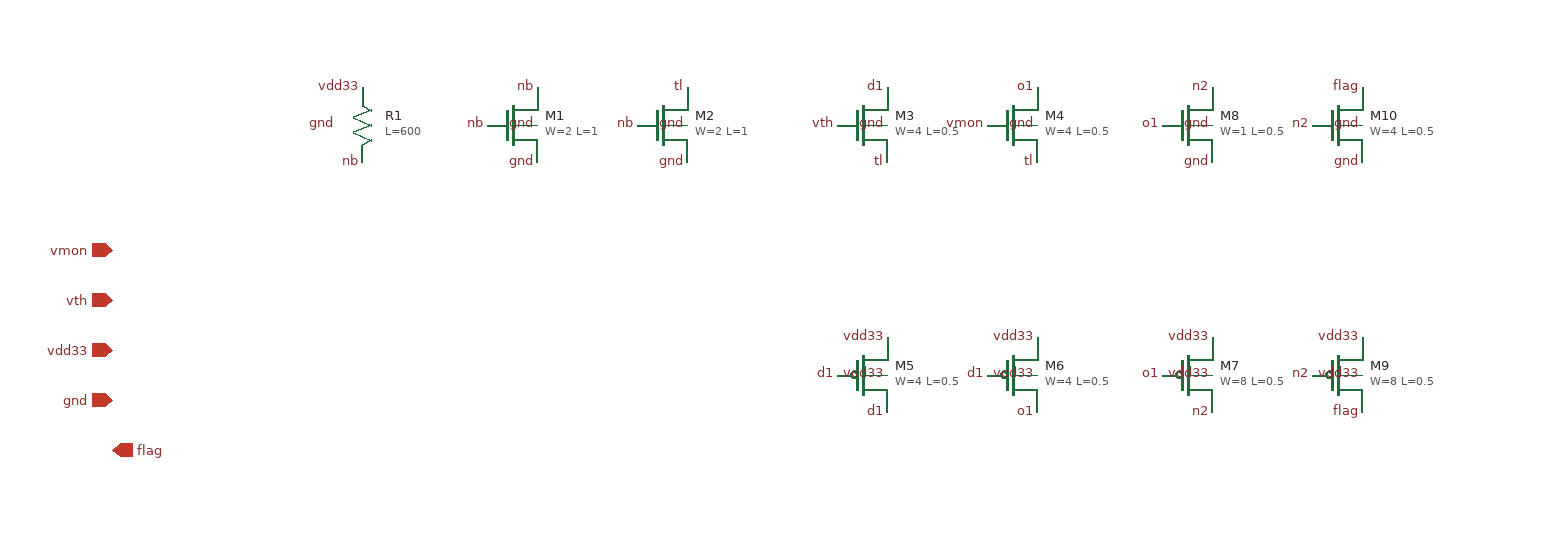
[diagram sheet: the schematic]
v {xschem version=3.4.7 file_version=1.2
}
G {}
K {}
V {}
S {}
E {}
C {sky130_fd_pr/res_xhigh_po_1p41.sym} 0 0 0 0 {name=R1 L=600 model=res_xhigh_po_1p41 spiceprefix=X mult=1}
C {devices/lab_pin.sym} 0 -30 0 0 {name=p1 sig_type=std_logic lab=vdd33}
C {devices/lab_pin.sym} 0 30 0 0 {name=p2 sig_type=std_logic lab=nb}
C {devices/lab_pin.sym} -20 0 0 0 {name=p3 sig_type=std_logic lab=gnd}
C {sky130_fd_pr/nfet_g5v0d10v5.sym} 120 0 0 0 {name=M1 L=1 W=2 nf=1 mult=1 model=nfet_g5v0d10v5 spiceprefix=X}
C {devices/lab_pin.sym} 140 -30 0 0 {name=p4 sig_type=std_logic lab=nb}
C {devices/lab_pin.sym} 100 0 0 0 {name=p5 sig_type=std_logic lab=nb}
C {devices/lab_pin.sym} 140 30 0 0 {name=p6 sig_type=std_logic lab=gnd}
C {devices/lab_pin.sym} 140 0 0 0 {name=p7 sig_type=std_logic lab=gnd}
C {sky130_fd_pr/nfet_g5v0d10v5.sym} 240 0 0 0 {name=M2 L=1 W=2 nf=1 mult=4 model=nfet_g5v0d10v5 spiceprefix=X}
C {devices/lab_pin.sym} 260 -30 0 0 {name=p8 sig_type=std_logic lab=tl}
C {devices/lab_pin.sym} 220 0 0 0 {name=p9 sig_type=std_logic lab=nb}
C {devices/lab_pin.sym} 260 30 0 0 {name=p10 sig_type=std_logic lab=gnd}
C {devices/lab_pin.sym} 260 0 0 0 {name=p11 sig_type=std_logic lab=gnd}
C {sky130_fd_pr/nfet_g5v0d10v5.sym} 400 0 0 0 {name=M3 L=0.5 W=4 nf=1 mult=1 model=nfet_g5v0d10v5 spiceprefix=X}
C {devices/lab_pin.sym} 420 -30 0 0 {name=p12 sig_type=std_logic lab=d1}
C {devices/lab_pin.sym} 380 0 0 0 {name=p13 sig_type=std_logic lab=vth}
C {devices/lab_pin.sym} 420 30 0 0 {name=p14 sig_type=std_logic lab=tl}
C {devices/lab_pin.sym} 420 0 0 0 {name=p15 sig_type=std_logic lab=gnd}
C {sky130_fd_pr/nfet_g5v0d10v5.sym} 520 0 0 0 {name=M4 L=0.5 W=4 nf=1 mult=1 model=nfet_g5v0d10v5 spiceprefix=X}
C {devices/lab_pin.sym} 540 -30 0 0 {name=p16 sig_type=std_logic lab=o1}
C {devices/lab_pin.sym} 500 0 0 0 {name=p17 sig_type=std_logic lab=vmon}
C {devices/lab_pin.sym} 540 30 0 0 {name=p18 sig_type=std_logic lab=tl}
C {devices/lab_pin.sym} 540 0 0 0 {name=p19 sig_type=std_logic lab=gnd}
C {sky130_fd_pr/pfet_g5v0d10v5.sym} 400 200 0 0 {name=M5 L=0.5 W=4 nf=1 mult=1 model=pfet_g5v0d10v5 spiceprefix=X}
C {devices/lab_pin.sym} 420 170 0 0 {name=p20 sig_type=std_logic lab=vdd33}
C {devices/lab_pin.sym} 380 200 0 0 {name=p21 sig_type=std_logic lab=d1}
C {devices/lab_pin.sym} 420 230 0 0 {name=p22 sig_type=std_logic lab=d1}
C {devices/lab_pin.sym} 420 200 0 0 {name=p23 sig_type=std_logic lab=vdd33}
C {sky130_fd_pr/pfet_g5v0d10v5.sym} 520 200 0 0 {name=M6 L=0.5 W=4 nf=1 mult=1 model=pfet_g5v0d10v5 spiceprefix=X}
C {devices/lab_pin.sym} 540 170 0 0 {name=p24 sig_type=std_logic lab=vdd33}
C {devices/lab_pin.sym} 500 200 0 0 {name=p25 sig_type=std_logic lab=d1}
C {devices/lab_pin.sym} 540 230 0 0 {name=p26 sig_type=std_logic lab=o1}
C {devices/lab_pin.sym} 540 200 0 0 {name=p27 sig_type=std_logic lab=vdd33}
C {sky130_fd_pr/pfet_g5v0d10v5.sym} 660 200 0 0 {name=M7 L=0.5 W=8 nf=1 mult=1 model=pfet_g5v0d10v5 spiceprefix=X}
C {devices/lab_pin.sym} 680 170 0 0 {name=p28 sig_type=std_logic lab=vdd33}
C {devices/lab_pin.sym} 640 200 0 0 {name=p29 sig_type=std_logic lab=o1}
C {devices/lab_pin.sym} 680 230 0 0 {name=p30 sig_type=std_logic lab=n2}
C {devices/lab_pin.sym} 680 200 0 0 {name=p31 sig_type=std_logic lab=vdd33}
C {sky130_fd_pr/nfet_g5v0d10v5.sym} 660 0 0 0 {name=M8 L=0.5 W=1 nf=1 mult=1 model=nfet_g5v0d10v5 spiceprefix=X}
C {devices/lab_pin.sym} 680 -30 0 0 {name=p32 sig_type=std_logic lab=n2}
C {devices/lab_pin.sym} 640 0 0 0 {name=p33 sig_type=std_logic lab=o1}
C {devices/lab_pin.sym} 680 30 0 0 {name=p34 sig_type=std_logic lab=gnd}
C {devices/lab_pin.sym} 680 0 0 0 {name=p35 sig_type=std_logic lab=gnd}
C {sky130_fd_pr/pfet_g5v0d10v5.sym} 780 200 0 0 {name=M9 L=0.5 W=8 nf=1 mult=1 model=pfet_g5v0d10v5 spiceprefix=X}
C {devices/lab_pin.sym} 800 170 0 0 {name=p36 sig_type=std_logic lab=vdd33}
C {devices/lab_pin.sym} 760 200 0 0 {name=p37 sig_type=std_logic lab=n2}
C {devices/lab_pin.sym} 800 230 0 0 {name=p38 sig_type=std_logic lab=flag}
C {devices/lab_pin.sym} 800 200 0 0 {name=p39 sig_type=std_logic lab=vdd33}
C {sky130_fd_pr/nfet_g5v0d10v5.sym} 780 0 0 0 {name=M10 L=0.5 W=4 nf=1 mult=1 model=nfet_g5v0d10v5 spiceprefix=X}
C {devices/lab_pin.sym} 800 -30 0 0 {name=p40 sig_type=std_logic lab=flag}
C {devices/lab_pin.sym} 760 0 0 0 {name=p41 sig_type=std_logic lab=n2}
C {devices/lab_pin.sym} 800 30 0 0 {name=p42 sig_type=std_logic lab=gnd}
C {devices/lab_pin.sym} 800 0 0 0 {name=p43 sig_type=std_logic lab=gnd}
C {devices/ipin.sym} -200 100 0 0 {name=p44 lab=vmon}
C {devices/ipin.sym} -200 140 0 0 {name=p45 lab=vth}
C {devices/iopin.sym} -200 180 0 0 {name=p46 lab=vdd33}
C {devices/iopin.sym} -200 220 0 0 {name=p47 lab=gnd}
C {devices/opin.sym} -200 260 0 0 {name=p48 lab=flag}
